# Generated by FakeRAM 2.0
VERSION 5.7 ;
BUSBITCHARS "[]" ;
PROPERTYDEFINITIONS
  MACRO width INTEGER ;
  MACRO depth INTEGER ;
  MACRO banks INTEGER ;
END PROPERTYDEFINITIONS
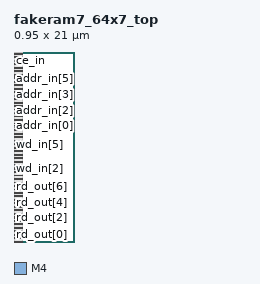
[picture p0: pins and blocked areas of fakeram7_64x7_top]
MACRO fakeram7_64x7_top
  PROPERTY width 7 ;
  PROPERTY depth 64 ;
  PROPERTY banks 1 ;
  FOREIGN fakeram7_64x7_top 0 0 ;
  SYMMETRY X Y R90 ;
  SIZE 0.9500 BY 21.0000 ;
  CLASS BLOCK ;
  PIN rd_out[0]
    DIRECTION OUTPUT ;
    USE SIGNAL ;
    PORT
      LAYER M4 ;
      RECT 0.00000 0.04800 0.02400 0.07200 ;
    END
  END rd_out[0]
  PIN rd_out[1]
    DIRECTION OUTPUT ;
    USE SIGNAL ;
    PORT
      LAYER M4 ;
      RECT 0.00000 0.91200 0.02400 0.93600 ;
    END
  END rd_out[1]
  PIN rd_out[2]
    DIRECTION OUTPUT ;
    USE SIGNAL ;
    PORT
      LAYER M4 ;
      RECT 0.00000 1.77600 0.02400 1.80000 ;
    END
  END rd_out[2]
  PIN rd_out[3]
    DIRECTION OUTPUT ;
    USE SIGNAL ;
    PORT
      LAYER M4 ;
      RECT 0.00000 2.64000 0.02400 2.66400 ;
    END
  END rd_out[3]
  PIN rd_out[4]
    DIRECTION OUTPUT ;
    USE SIGNAL ;
    PORT
      LAYER M4 ;
      RECT 0.00000 3.50400 0.02400 3.52800 ;
    END
  END rd_out[4]
  PIN rd_out[5]
    DIRECTION OUTPUT ;
    USE SIGNAL ;
    PORT
      LAYER M4 ;
      RECT 0.00000 4.36800 0.02400 4.39200 ;
    END
  END rd_out[5]
  PIN rd_out[6]
    DIRECTION OUTPUT ;
    USE SIGNAL ;
    PORT
      LAYER M4 ;
      RECT 0.00000 5.23200 0.02400 5.25600 ;
    END
  END rd_out[6]
  PIN wd_in[0]
    DIRECTION INPUT ;
    USE SIGNAL ;
    PORT
      LAYER M4 ;
      RECT 0.00000 6.43200 0.02400 6.45600 ;
    END
  END wd_in[0]
  PIN wd_in[1]
    DIRECTION INPUT ;
    USE SIGNAL ;
    PORT
      LAYER M4 ;
      RECT 0.00000 7.29600 0.02400 7.32000 ;
    END
  END wd_in[1]
  PIN wd_in[2]
    DIRECTION INPUT ;
    USE SIGNAL ;
    PORT
      LAYER M4 ;
      RECT 0.00000 8.16000 0.02400 8.18400 ;
    END
  END wd_in[2]
  PIN wd_in[3]
    DIRECTION INPUT ;
    USE SIGNAL ;
    PORT
      LAYER M4 ;
      RECT 0.00000 9.02400 0.02400 9.04800 ;
    END
  END wd_in[3]
  PIN wd_in[4]
    DIRECTION INPUT ;
    USE SIGNAL ;
    PORT
      LAYER M4 ;
      RECT 0.00000 9.88800 0.02400 9.91200 ;
    END
  END wd_in[4]
  PIN wd_in[5]
    DIRECTION INPUT ;
    USE SIGNAL ;
    PORT
      LAYER M4 ;
      RECT 0.00000 10.75200 0.02400 10.77600 ;
    END
  END wd_in[5]
  PIN wd_in[6]
    DIRECTION INPUT ;
    USE SIGNAL ;
    PORT
      LAYER M4 ;
      RECT 0.00000 11.61600 0.02400 11.64000 ;
    END
  END wd_in[6]
  PIN addr_in[0]
    DIRECTION INPUT ;
    USE SIGNAL ;
    PORT
      LAYER M4 ;
      RECT 0.00000 12.81600 0.02400 12.84000 ;
    END
  END addr_in[0]
  PIN addr_in[1]
    DIRECTION INPUT ;
    USE SIGNAL ;
    PORT
      LAYER M4 ;
      RECT 0.00000 13.68000 0.02400 13.70400 ;
    END
  END addr_in[1]
  PIN addr_in[2]
    DIRECTION INPUT ;
    USE SIGNAL ;
    PORT
      LAYER M4 ;
      RECT 0.00000 14.54400 0.02400 14.56800 ;
    END
  END addr_in[2]
  PIN addr_in[3]
    DIRECTION INPUT ;
    USE SIGNAL ;
    PORT
      LAYER M4 ;
      RECT 0.00000 15.40800 0.02400 15.43200 ;
    END
  END addr_in[3]
  PIN addr_in[4]
    DIRECTION INPUT ;
    USE SIGNAL ;
    PORT
      LAYER M4 ;
      RECT 0.00000 16.27200 0.02400 16.29600 ;
    END
  END addr_in[4]
  PIN addr_in[5]
    DIRECTION INPUT ;
    USE SIGNAL ;
    PORT
      LAYER M4 ;
      RECT 0.00000 17.13600 0.02400 17.16000 ;
    END
  END addr_in[5]
  PIN we_in
    DIRECTION INPUT ;
    USE SIGNAL ;
    PORT
      LAYER M4 ;
      RECT 0.00000 18.33600 0.02400 18.36000 ;
    END
  END we_in
  PIN clk
    DIRECTION INPUT ;
    USE SIGNAL ;
    PORT
      LAYER M4 ;
      RECT 0.00000 19.20000 0.02400 19.22400 ;
    END
  END clk
  PIN ce_in
    DIRECTION INPUT ;
    USE SIGNAL ;
    PORT
      LAYER M4 ;
      RECT 0.00000 20.06400 0.02400 20.08800 ;
    END
  END ce_in
  PIN VDD
    DIRECTION INOUT ;
    USE POWER ;
    PORT
      LAYER M4 ;
      RECT 0.04800 0.38400 0.90200 0.48000 ;
      RECT 0.04800 1.15200 0.90200 1.24800 ;
      RECT 0.04800 1.92000 0.90200 2.01600 ;
      RECT 0.04800 2.68800 0.90200 2.78400 ;
      RECT 0.04800 3.45600 0.90200 3.55200 ;
      RECT 0.04800 4.22400 0.90200 4.32000 ;
      RECT 0.04800 4.99200 0.90200 5.08800 ;
      RECT 0.04800 5.76000 0.90200 5.85600 ;
      RECT 0.04800 6.52800 0.90200 6.62400 ;
      RECT 0.04800 7.29600 0.90200 7.39200 ;
      RECT 0.04800 8.06400 0.90200 8.16000 ;
      RECT 0.04800 8.83200 0.90200 8.92800 ;
      RECT 0.04800 9.60000 0.90200 9.69600 ;
      RECT 0.04800 10.36800 0.90200 10.46400 ;
      RECT 0.04800 11.13600 0.90200 11.23200 ;
      RECT 0.04800 11.90400 0.90200 12.00000 ;
      RECT 0.04800 12.67200 0.90200 12.76800 ;
      RECT 0.04800 13.44000 0.90200 13.53600 ;
      RECT 0.04800 14.20800 0.90200 14.30400 ;
      RECT 0.04800 14.97600 0.90200 15.07200 ;
      RECT 0.04800 15.74400 0.90200 15.84000 ;
      RECT 0.04800 16.51200 0.90200 16.60800 ;
      RECT 0.04800 17.28000 0.90200 17.37600 ;
      RECT 0.04800 18.04800 0.90200 18.14400 ;
      RECT 0.04800 18.81600 0.90200 18.91200 ;
      RECT 0.04800 19.58400 0.90200 19.68000 ;
      RECT 0.04800 20.35200 0.90200 20.44800 ;
    END
  END VDD
  PIN VSS
    DIRECTION INOUT ;
    USE GROUND ;
    PORT
      LAYER M4 ;
      RECT 0.04800 0.00000 0.90200 0.09600 ;
      RECT 0.04800 0.76800 0.90200 0.86400 ;
      RECT 0.04800 1.53600 0.90200 1.63200 ;
      RECT 0.04800 2.30400 0.90200 2.40000 ;
      RECT 0.04800 3.07200 0.90200 3.16800 ;
      RECT 0.04800 3.84000 0.90200 3.93600 ;
      RECT 0.04800 4.60800 0.90200 4.70400 ;
      RECT 0.04800 5.37600 0.90200 5.47200 ;
      RECT 0.04800 6.14400 0.90200 6.24000 ;
      RECT 0.04800 6.91200 0.90200 7.00800 ;
      RECT 0.04800 7.68000 0.90200 7.77600 ;
      RECT 0.04800 8.44800 0.90200 8.54400 ;
      RECT 0.04800 9.21600 0.90200 9.31200 ;
      RECT 0.04800 9.98400 0.90200 10.08000 ;
      RECT 0.04800 10.75200 0.90200 10.84800 ;
      RECT 0.04800 11.52000 0.90200 11.61600 ;
      RECT 0.04800 12.28800 0.90200 12.38400 ;
      RECT 0.04800 13.05600 0.90200 13.15200 ;
      RECT 0.04800 13.82400 0.90200 13.92000 ;
      RECT 0.04800 14.59200 0.90200 14.68800 ;
      RECT 0.04800 15.36000 0.90200 15.45600 ;
      RECT 0.04800 16.12800 0.90200 16.22400 ;
      RECT 0.04800 16.89600 0.90200 16.99200 ;
      RECT 0.04800 17.66400 0.90200 17.76000 ;
      RECT 0.04800 18.43200 0.90200 18.52800 ;
      RECT 0.04800 19.20000 0.90200 19.29600 ;
      RECT 0.04800 19.96800 0.90200 20.06400 ;
      RECT 0.04800 20.73600 0.90200 20.83200 ;
    END
  END VSS
  OBS
    LAYER M1 ;
    RECT 0 0 0.95000 21.00000 ;
    LAYER M2 ;
    RECT 0 0 0.95000 21.00000 ;
    LAYER M3 ;
    RECT 0 0 0.95000 21.00000 ;
  END
END fakeram7_64x7_top

END LIBRARY
